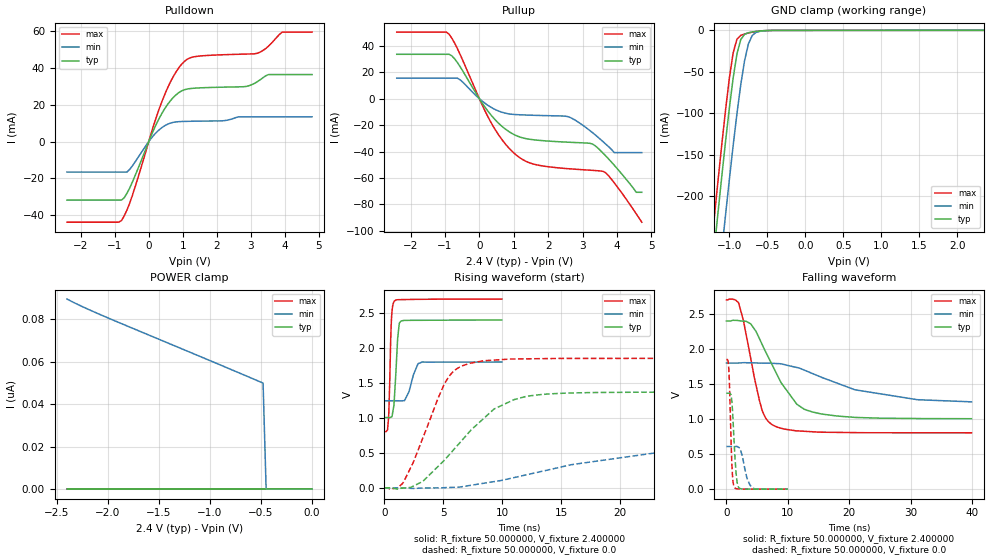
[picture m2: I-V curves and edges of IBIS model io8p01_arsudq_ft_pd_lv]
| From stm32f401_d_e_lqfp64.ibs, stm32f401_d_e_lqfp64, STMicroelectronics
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|   Model io8p01_arsudq_ft_pd_lv
[Model]  io8p01_arsudq_ft_pd_lv
Model_type I/O
Polarity   Non-Inverting
Enable   Active-Low
Vinl =   0.720000V
Vinh =   1.680000V
Vmeas =  1.200000V
Cref =   50.000000pF
Rref =   100.000000M
Vref =   0.0V
C_comp   2.239000pF   2.178700pF   2.334000pF
[Temperature Range]   25.000000   0.125000k   -40.000000
[Pullup Reference]   2.400000V   1.800000V   2.700000V
[Pulldown Reference]   0.0V   0.0V   0.0V
[POWER Clamp Reference]   2.400000V   1.800000V   2.700000V
[GND Clamp Reference]   0.0V   0.0V   0.0V
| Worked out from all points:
|   slope of the pulldown table from 0 to 0.36 V, typ, clamps not added: 25 ohm
|   slope of the pullup table from 0 to 0.36 V, typ, clamps not added: 27.7 ohm
|   GND clamp passes 1 mA (typ) near -0.62 V on its own axis
|   rising waveform, R_fixture 50.000000, V_fixture 2.400000: 20-80 % time 273ps typ, 608ps min, 183ps max; typ from 1 V to 2.4 V
|   rising waveform, R_fixture 50.000000, V_fixture 0.0: 20-80 % time 4.75ns typ, 12.1ns min, 2.62ns max; typ from 0 V to 1.37 V
|   falling waveform, R_fixture 50.000000, V_fixture 2.400000: 20-80 % time 5.34ns typ, 12.4ns min, 2.67ns max; typ from 2.4 V to 1 V
|   falling waveform, R_fixture 50.000000, V_fixture 0.0: 20-80 % time 523ps typ, 975ps min, 383ps max; typ from 1.37 V to 0 V
[Pulldown]
|Voltage   I(typ)   I(min)   I(max)
-2.4V     -31.73mA   -16.51mA   -43.74mA
-800mV    -31.73mA   -16.51mA   -42.87mA
-480mV    -21.98mA   -13.17mA   -29.2mA
80mV      3.63mA     1.966mA    5.014mA
480mV     18.15mA    8.738mA    26.02mA
800mV     25.38mA    10.72mA    37.77mA
1.12V     28.53mA    11.02mA    44.6mA
2.8V      29.84mA    13.49mA    47.53mA
3.2V      32.65mA    13.49mA    48.04mA
3.52V     36.42mA    13.49mA    51.83mA
3.92V     36.42mA    13.49mA    59.49mA
4.8V      36.42mA    13.49mA    59.49mA
[Pullup]
|Voltage   I(typ)   I(min)   I(max)
-2.4V     33.57mA    15.56mA    50.37mA
-960mV    33.57mA    15.56mA    50.37mA
-560mV    24.29mA    14.3mA     33.54mA
320mV     -11.75mA   -6.207mA   -17.08mA
960mV     -26.47mA   -11.82mA   -40.02mA
1.52V     -30.88mA   -12.51mA   -49.05mA
2.56V     -32.88mA   -13.48mA   -52.9mA
3.28V     -34.19mA   -25.52mA   -54.18mA
3.6V      -41.31mA   -32.62mA   -54.97mA
3.92V     -50.32mA   -40.8mA    -63.63mA
4.56V     -70.8mA    -40.8mA    -87.08mA
4.72V     -70.8mA    -40.8mA    -93.4mA
[GND_clamp]
|Voltage   I(typ)   I(min)   I(max)
-2.4V     -1.424A    -1.508A    -1.393A
-1.25V    -311.2mA   -401.9mA   -273.3mA
-1.2V     -265.4mA   -356.1mA   -227.2mA
-1.15V    -220.4mA   -310.8mA   -181.9mA
-1.1V     -176.3mA   -266.2mA   -137.9mA
-1.05V    -133.8mA   -222.5mA   -95.87mA
-950mV    -57.3mA    -138.9mA   -26.99mA
-900mV    -28.28mA   -100.4mA   -10.6mA
-850mV    -11.02mA   -65.54mA   -5.972mA
-750mV    -2.846mA   -16.51mA   -3.192mA
-600mV    -761.3uA   -1.173mA   -751.9uA
2.35V     58.09uA    37.92uA    67.25uA
[POWER_clamp]
|Voltage   I(typ)   I(min)   I(max)
-2.4V     0A         89.62nA    0A
-2.04V    0A         81.57nA    0A
-480mV    0A         50.01nA    0A
-450mV    0A         0A         0A
0V        0A         0A         0A
[Ramp]
| variable   typ   min   max
dV/dt_r  0.82152/4.74213n   0.38416/12.99157n   1.11042/2.61781n
dV/dt_f  0.83670/5.33977n   0.32376/13.28857n   1.13725/2.66768n
R_load = 50.000000
[Rising Waveform]
R_fixture= 50.000000
V_fixture= 2.400000
V_fixture_min= 1.800000
V_fixture_max= 2.700000
|time   V(typ)   V(min)   V(max)
0s        1.005V     1.245V     804.2mV
260.3ps   1.005V     1.245V     830.5mV
340.3ps   1.005V     1.245V     987.8mV
600.6ps   1.014V     1.246V     2.438V
860.9ps   1.34V      1.246V     2.673V
1.121ns   2.14V      1.245V     2.689V
1.381ns   2.381V     1.244V     2.691V
1.702ns   2.393V     1.247V     2.692V
3.203ns   2.395V     1.798V     2.695V
9.97ns    2.399V     1.799V     2.699V
[Rising Waveform]
R_fixture= 50.000000
V_fixture= 0.0
V_fixture_min= 0.0
V_fixture_max= 0.0
|time   V(typ)   V(min)   V(max)
0s        177.9uV    73.82uV    444.9uV
1.602ns   -2.703mV   -101.8uV   77.61mV
3.283ns   97.05mV    -696uV     724.2mV
5.125ns   402.4mV    3.293mV    1.495V
6.006ns   570.2mV    9.466mV    1.685V
7.207ns   799mV      33.58mV    1.779V
9.369ns   1.132V     91.51mV    1.827V
12.97ns   1.328V     221.5mV    1.846V
24.82ns   1.368V     542.6mV    1.851V
39.88ns   1.369V     608.4mV    1.851V
[Falling Waveform]
R_fixture= 50.000000
V_fixture= 2.400000
V_fixture_min= 1.800000
V_fixture_max= 2.700000
|time   V(typ)   V(min)   V(max)
0s        2.399V     1.799V     2.699V
2.002ns   2.404V     1.8V       2.651V
2.723ns   2.397V     1.804V     2.42V
3.924ns   2.36V      1.803V     1.879V
5.766ns   2.073V     1.798V     1.136V
7.608ns   1.743V     1.794V     911.8mV
11.45ns   1.212V     1.735V     831.9mV
14.01ns   1.101V     1.649V     818.9mV
20.9ns    1.024V     1.418V     806.9mV
39.88ns   1.005V     1.245V     804.2mV
[Falling Waveform]
R_fixture= 50.000000
V_fixture= 0.0
V_fixture_min= 0.0
V_fixture_max= 0.0
|time   V(typ)   V(min)   V(max)
0s        1.369V     608.4mV    1.851V
380.4ps   1.369V     608.4mV    1.719V
480.5ps   1.369V     608.4mV    1.521V
880.9ps   1.256V     608.2mV    361.2mV
1.061ns   1.003V     607.9mV    113.6mV
1.281ns   621mV      607.8mV    30.48mV
1.702ns   117.8mV    609.9mV    5.129mV
2.062ns   17.65mV    592.9mV    2.785mV
3.864ns   962.7uV    52.6mV     1.34mV
9.97ns    177.9uV    73.82uV    444.9uV
